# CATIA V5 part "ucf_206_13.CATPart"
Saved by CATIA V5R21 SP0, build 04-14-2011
Part number: ucf_206_13
Bounding box of the stored display mesh (mm): x 6.863 to 16.388, y -4.762 to 4.762, z 15.373 to 24.898
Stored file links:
  C:\TPO v2\SharedFS\Outgoing\ucf_206_13.CATPart

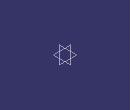
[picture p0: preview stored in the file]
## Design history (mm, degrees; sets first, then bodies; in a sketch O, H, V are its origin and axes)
AxisSystem1: origin (0, 0, 0), X (1, 0, 0), Y (0, 1, 0), Z (0, 0, 1)
Body1 "ucf_206_13" (main body)
  Solid1: solid without history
